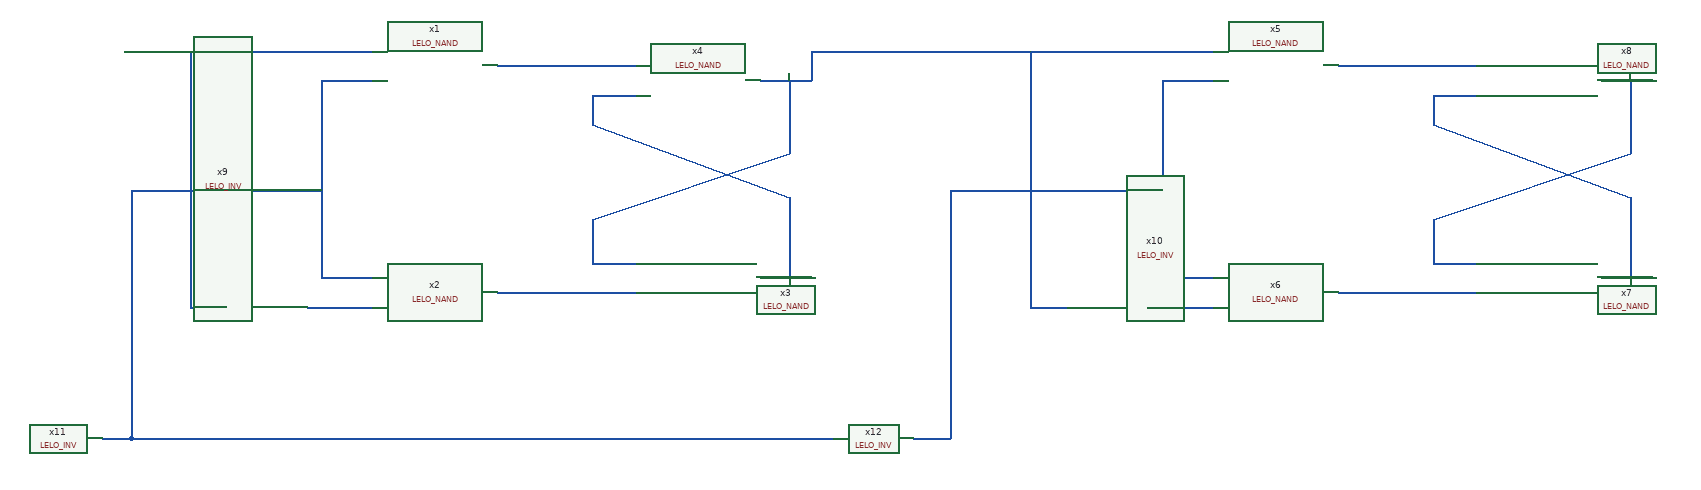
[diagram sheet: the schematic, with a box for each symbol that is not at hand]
v {xschem version=3.4.8RC file_version=1.2}
G {}
K {}
V {}
S {}
E {}
N -120 180 70 180 {lab=#net1}
N -120 -130 70 -130 {lab=#net2}
N 240 -110 310 -110 {lab=#net3}
N 280 -110 280 -10 {lab=#net3}
N 10 80 280 -10 {lab=#net3}
N 10 80 10 140 {lab=#net3}
N 10 140 70 140 {lab=#net3}
N 240 160 310 160 {lab=#net4}
N 280 50 280 160 {lab=#net4}
N 10 -50 280 50 {lab=#net4}
N 10 -90 10 -50 {lab=#net4}
N 10 -90 70 -90 {lab=#net4}
N -630 -150 -290 -150 {lab=#net5}
N -540 -150 -540 200 {lab=#net5}
N -540 200 -490 200 {lab=#net5}
N -380 200 -290 200 {lab=#net6}
N -360 160 -290 160 {lab=#net7}
N -360 -110 -360 160 {lab=#net7}
N -360 -110 -290 -110 {lab=#net7}
N -620 40 -360 40 {lab=#net7}
N -620 40 -620 380 {lab=#net7}
N -660 380 -620 380 {lab=#net7}
N 1030 180 1220 180 {lab=#net8}
N 1030 -130 1220 -130 {lab=#net9}
N 1390 -110 1460 -110 {lab=#net10}
N 1430 -110 1430 -10 {lab=#net10}
N 1160 80 1430 -10 {lab=#net10}
N 1160 80 1160 140 {lab=#net10}
N 1160 140 1220 140 {lab=#net10}
N 1390 160 1460 160 {lab=#net11}
N 1430 50 1430 160 {lab=#net11}
N 1160 -50 1430 50 {lab=#net11}
N 1160 -90 1160 -50 {lab=#net11}
N 1160 -90 1220 -90 {lab=#net11}
N 520 -150 860 -150 {lab=#net3}
N 610 -150 610 200 {lab=#net3}
N 610 200 660 200 {lab=#net3}
N 770 200 860 200 {lab=#net12}
N 790 160 860 160 {lab=#net13}
N 790 -110 790 160 {lab=#net13}
N 790 -110 860 -110 {lab=#net13}
N 530 40 790 40 {lab=#net13}
N 310 -150 310 -110 {lab=#net3}
N 310 -150 520 -150 {lab=#net3}
N -620 380 340 380 {lab=#net7}
N 450 380 500 380 {lab=#net13}
N 500 40 500 380 {lab=#net13}
N 500 40 530 40 {lab=#net13}
C {LELO_SVOD_SKY130A/LELO_NAND.sym} -210 -130 0 0 {name=x1}
C {LELO_SVOD_SKY130A/LELO_NAND.sym} -210 180 0 0 {name=x2}
C {LELO_SVOD_SKY130A/LELO_NAND.sym} 150 160 0 0 {name=x3}
C {LELO_SVOD_SKY130A/LELO_NAND.sym} 150 -110 0 0 {name=x4}
C {LELO_SVOD_SKY130A/LELO_INV.sym} -430 200 0 0 {name=x9}
C {LELO_SVOD_SKY130A/LELO_INV.sym} -710 380 0 0 {name=x11}
C {LELO_SVOD_SKY130A/LELO_NAND.sym} 940 -130 0 0 {name=x5}
C {LELO_SVOD_SKY130A/LELO_NAND.sym} 940 180 0 0 {name=x6}
C {LELO_SVOD_SKY130A/LELO_NAND.sym} 1300 160 0 0 {name=x7}
C {LELO_SVOD_SKY130A/LELO_NAND.sym} 1300 -110 0 0 {name=x8}
C {LELO_SVOD_SKY130A/LELO_INV.sym} 720 200 0 0 {name=x10}
C {LELO_SVOD_SKY130A/LELO_INV.sym} 400 380 0 0 {name=x12}
